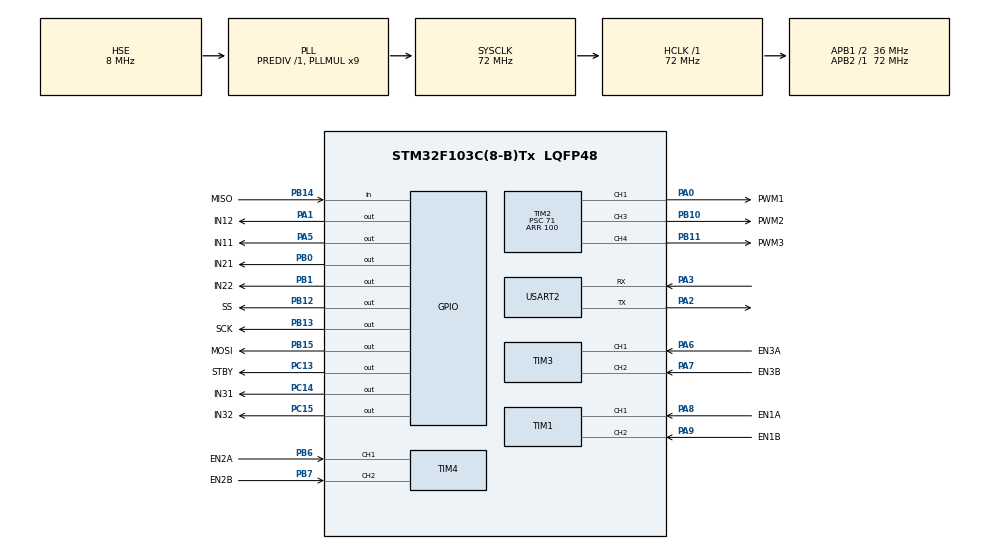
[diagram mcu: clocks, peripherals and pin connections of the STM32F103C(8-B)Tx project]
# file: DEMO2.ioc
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Dma.Request0=USART2_RX
Dma.USART2_RX.0.Direction=DMA_PERIPH_TO_MEMORY
Dma.USART2_RX.0.Instance=DMA1_Channel6
Dma.USART2_RX.0.MemDataAlignment=DMA_MDATAALIGN_BYTE
Dma.USART2_RX.0.MemInc=DMA_MINC_ENABLE
Dma.USART2_RX.0.Mode=DMA_CIRCULAR
Dma.USART2_RX.0.PeriphDataAlignment=DMA_PDATAALIGN_BYTE
Dma.USART2_RX.0.PeriphInc=DMA_PINC_DISABLE
Dma.USART2_RX.0.Priority=DMA_PRIORITY_LOW
Mcu.Family=STM32F1
Mcu.Name=STM32F103C(8-B)Tx
Mcu.Package=LQFP48
NVIC.DMA1_Channel6_IRQn=true\:0\:0\:true\:false\:true\:false\:true\:true
NVIC.PriorityGroup=NVIC_PRIORITYGROUP_4
NVIC.USART2_IRQn=true\:1\:0\:true\:false\:true\:true\:true\:true
PA0-WKUP.GPIO_Label=PWM1
PA0-WKUP.Signal=S_TIM2_CH1_ETR
PA1.GPIO_Label=IN12
PA1.Signal=GPIO_Output
PA13.Mode=Serial_Wire
PA13.Signal=SYS_JTMS-SWDIO
PA14.Mode=Serial_Wire
PA14.Signal=SYS_JTCK-SWCLK
PA2.Mode=Asynchronous
PA2.Signal=USART2_TX
PA3.Mode=Asynchronous
PA3.Signal=USART2_RX
PA5.GPIO_Label=IN11
PA5.Signal=GPIO_Output
PA6.GPIO_Label=EN3A
PA6.Signal=S_TIM3_CH1
PA7.GPIO_Label=EN3B
PA7.Signal=S_TIM3_CH2
PA8.GPIO_Label=EN1A
PA8.Signal=S_TIM1_CH1
PA9.GPIO_Label=EN1B
PA9.Signal=S_TIM1_CH2
PB0.GPIO_Label=IN21
PB0.Signal=GPIO_Output
PB1.GPIO_Label=IN22
PB1.Signal=GPIO_Output
PB10.GPIO_Label=PWM2
PB10.Signal=S_TIM2_CH3
PB11.GPIO_Label=PWM3
PB11.Signal=S_TIM2_CH4
PB12.GPIO_Label=SS
PB12.PinState=GPIO_PIN_SET
PB12.Signal=GPIO_Output
PB13.GPIO_Label=SCK
PB13.PinState=GPIO_PIN_SET
PB13.Signal=GPIO_Output
PB14.GPIO_Label=MISO
PB14.Signal=GPIO_Input
PB15.GPIO_Label=MOSI
PB15.PinState=GPIO_PIN_SET
PB15.Signal=GPIO_Output
PB6.GPIO_Label=EN2A
PB6.Signal=S_TIM4_CH1
PB7.GPIO_Label=EN2B
PB7.Signal=S_TIM4_CH2
PC13-TAMPER-RTC.GPIO_Label=STBY
PC13-TAMPER-RTC.Signal=GPIO_Output
PC14-OSC32_IN.GPIO_Label=IN31
PC14-OSC32_IN.Signal=GPIO_Output
PC15-OSC32_OUT.GPIO_Label=IN32
PC15-OSC32_OUT.Signal=GPIO_Output
PD0-OSC_IN.Mode=HSE-External-Oscillator
PD0-OSC_IN.Signal=RCC_OSC_IN
PD1-OSC_OUT.Mode=HSE-External-Oscillator
PD1-OSC_OUT.Signal=RCC_OSC_OUT
ProjectManager.HeapSize=0x200
ProjectManager.StackSize=0x400
ProjectManager.TargetToolchain=MDK-ARM V5
RCC.AHBFreq_Value=72000000
RCC.APB1CLKDivider=RCC_HCLK_DIV2
RCC.APB1Freq_Value=36000000
RCC.APB1TimFreq_Value=72000000
RCC.APB2Freq_Value=72000000
RCC.APB2TimFreq_Value=72000000
RCC.HCLKFreq_Value=72000000
RCC.PLLMUL=RCC_PLL_MUL9
RCC.PLLSourceVirtual=RCC_PLLSOURCE_HSE
RCC.SYSCLKFreq_VALUE=72000000
RCC.SYSCLKSource=RCC_SYSCLKSOURCE_PLLCLK
RCC.USBFreq_Value=72000000
SH.S_TIM1_CH1.0=TIM1_CH1,Encoder_Interface
SH.S_TIM1_CH2.0=TIM1_CH2,Encoder_Interface
SH.S_TIM2_CH1_ETR.0=TIM2_CH1,PWM Generation1 CH1
SH.S_TIM2_CH3.0=TIM2_CH3,PWM Generation3 CH3
SH.S_TIM2_CH4.0=TIM2_CH4,PWM Generation4 CH4
SH.S_TIM3_CH1.0=TIM3_CH1,Encoder_Interface
SH.S_TIM3_CH2.0=TIM3_CH2,Encoder_Interface
SH.S_TIM4_CH1.0=TIM4_CH1,Encoder_Interface
SH.S_TIM4_CH2.0=TIM4_CH2,Encoder_Interface
TIM1.AutoReloadPreload=TIM_AUTORELOAD_PRELOAD_ENABLE
TIM1.EncoderMode=TIM_ENCODERMODE_TI12
TIM2.AutoReloadPreload=TIM_AUTORELOAD_PRELOAD_ENABLE
TIM2.Channel-PWM\ Generation1\ CH1=TIM_CHANNEL_1
TIM2.Channel-PWM\ Generation3\ CH3=TIM_CHANNEL_3
TIM2.Channel-PWM\ Generation4\ CH4=TIM_CHANNEL_4
TIM2.Period=100
TIM2.Prescaler=71
TIM3.AutoReloadPreload=TIM_AUTORELOAD_PRELOAD_ENABLE
TIM3.EncoderMode=TIM_ENCODERMODE_TI12
TIM4.AutoReloadPreload=TIM_AUTORELOAD_PRELOAD_ENABLE
TIM4.EncoderMode=TIM_ENCODERMODE_TI12
USART2.VirtualMode=VM_ASYNC
VP_TIM2_VS_ClockSourceINT.Mode=Internal
board=custom

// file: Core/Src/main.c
/* USER CODE BEGIN Header */
/**
  ******************************************************************************
  * @file           : main.c
  * @brief          : Main program body
  ******************************************************************************
  * @attention
  *
  * Copyright (c) 2023 STMicroelectronics.
  * All rights reserved.
  *
  * This software is licensed under terms that can be found in the LICENSE file
  * in the root directory of this software component.
  * If no LICENSE file comes with this software, it is provided AS-IS.
  *
  ******************************************************************************
  */
/* USER CODE END Header */
#include "main.h"
#include "pwm.h"
#include "stdio.h"
#include <math.h>
//receive transmit
uint8_t RxBuffer[13];
char TxBuffer[12];
uint16_t i;
uint8_t R=100;
uint8_t r=29;

//input value
//encoder motor value
encoder MOTOR1 = {0,0,0};
encoder MOTOR2 = {0,0,0};
encoder MOTOR3 = {0,0,0};

//PID value
PID PID_1={0.761,21.798,0,0,0,0,0};
PID PID_2={0.809,22.685,0,0,0,0,0};
PID PID_3={0.848,23.505,0,0,0,0,0};

//output value
bot bot1 = {0,0,0};
bot bot2 = {0,0,0};
bot bot3 = {0,0,0};
uint8_t predir0=0,dir0=0;
//reading value
uint32_t timstart;
uint8_t count=30;
uint8_t countt=0;
TIM_HandleTypeDef htim1;
TIM_HandleTypeDef htim2;
TIM_HandleTypeDef htim3;
TIM_HandleTypeDef htim4;

UART_HandleTypeDef huart2;
DMA_HandleTypeDef hdma_usart2_rx;

void SystemClock_Config(void);
static void MX_GPIO_Init(void);
static void MX_DMA_Init(void);
static void MX_TIM1_Init(void);
static void MX_TIM2_Init(void);
static void MX_TIM3_Init(void);
static void MX_TIM4_Init(void);
static void MX_USART2_UART_Init(void);
void receive_value(bot* m1,bot* m2, bot* m3);

int main(void)
{

  /* MCU Configuration--------------------------------------------------------*/

  /* Reset of all peripherals, Initializes the Flash interface and the Systick. */
  HAL_Init();

  /* Configure the system clock */
  SystemClock_Config();

  /* Initialize all configured peripherals */
  MX_GPIO_Init();
  MX_DMA_Init();
  MX_TIM1_Init();
  MX_TIM2_Init();
  MX_TIM3_Init();
  MX_TIM4_Init();
  MX_USART2_UART_Init();
  /* USER CODE BEGIN 2 */
	HAL_TIM_Encoder_Start(&htim1, TIM_CHANNEL_ALL);
	HAL_TIM_Encoder_Start(&htim2, TIM_CHANNEL_ALL);
	HAL_TIM_Encoder_Start(&htim3, TIM_CHANNEL_ALL);
	HAL_TIM_Encoder_Start(&htim4, TIM_CHANNEL_ALL);
	HAL_TIM_PWM_Start(&htim2,TIM_CHANNEL_1);
	HAL_TIM_PWM_Start(&htim2,TIM_CHANNEL_3);
	HAL_TIM_PWM_Start(&htim2,TIM_CHANNEL_4);
	HAL_UART_Receive_DMA(&huart2, RxBuffer, 13);
  /* USER CODE END 2 */

  /* Infinite loop */
  /* USER CODE BEGIN WHILE */
	timstart = HAL_GetTick();
  while (1)
  {
    /* USER CODE END WHILE */
		timeinterrupt();
  }
}
/**
  * @brief Receive value using UART interface
  * @unit RPM
  * @retval uint8_t
  */
void receive_value(bot* m1,bot* m2, bot* m3)
{
	predir0=dir0;
	m1->dir=RxBuffer[0]-48;
	m1->vel=(RxBuffer[1]-48)*100+(RxBuffer[2]-48)*10+(RxBuffer[3]-48)-100;
	m2->dir=RxBuffer[4]-48;
	m2->vel=(RxBuffer[5]-48)*100+(RxBuffer[6]-48)*10+(RxBuffer[7]-48)-100;
	m3->dir=RxBuffer[8]-48;
	m3->vel=(RxBuffer[9]-48)*100+(RxBuffer[10]-48)*10+(RxBuffer[11]-48)-100;
	dir0=RxBuffer[12]-48;
	if (m1->vel>333) m1->vel=0;
	if (m2->vel>333) m2->vel=0;
	if (m3->vel>333) m3->vel=0;
}

/**
  * @brief Transmit velocity value to ROS
  * @unit void
  */

void vel_convert(char* vel_pub)
{
	if (bot1.dir == 0) bot1.cd = '0'; else bot1.cd = '1';
	if (bot2.dir == 0) bot2.cd = '0'; else bot2.cd = '1';
	if (bot3.dir == 0) bot3.cd = '0'; else bot3.cd = '1';
	bot1.iw=round(MOTOR1.w+100);
	bot2.iw=round(MOTOR2.w+100);
	bot3.iw=round(MOTOR3.w+100);
	sprintf(vel_pub, "%c%d%c%d%c%d", bot1.cd, bot1.iw, bot2.cd, bot2.iw, bot3.cd, bot3.iw);
	HAL_UART_Transmit_IT(&huart2, vel_pub, 12);
}

/**
  * @brief Systick Timer Interrupt after 0.01s
  * @unit second
  */
void timeinterrupt(void)
{
  uint32_t wait = 10;

  /* Add a freq to guarantee minimum wait */
  if (wait < HAL_MAX_DELAY)
  {
    wait += (uint32_t)(uwTickFreq);
  }
  if ((HAL_GetTick() - timstart) == wait)
  {
		receive_value(&bot1,&bot2,&bot3);
		if ((dir0==1 && predir0==2) || (dir0==2 && predir0==1))	count=0;
		if (count<20)
		{
			ballkeeping(dir0); // 2 - len(da bong) , 1- xuong(do bong)
			count++;
		}
		else 	ballkeeping(3);
		encoder_reading(&MOTOR1,&MOTOR2,&MOTOR3);
		bot1.pulse = PID_motor(&PID_1,bot1.vel,&MOTOR1)*10;
		bot2.pulse = PID_motor(&PID_2,bot2.vel,&MOTOR2)*10;
		bot3.pulse = PID_motor(&PID_3,bot3.vel,&MOTOR3)*10;
		control(bot1.pulse,bot2.pulse,bot3.pulse,bot1.dir,bot2.dir,bot3.dir);
		if (countt>=10)
			{
				vel_convert(TxBuffer);
				countt=0;
			}
		else countt++;
		timstart = HAL_GetTick();
  }
}
void HAL_UART_TxCpltCallback(UART_HandleTypeDef *huart)
{
   // do nothing here
}
void SystemClock_Config(void)
{
  RCC_OscInitTypeDef RCC_OscInitStruct = {0};
  RCC_ClkInitTypeDef RCC_ClkInitStruct = {0};

  /** Initializes the RCC Oscillators according to the specified parameters
  * in the RCC_OscInitTypeDef structure.
  */
  RCC_OscInitStruct.OscillatorType = RCC_OSCILLATORTYPE_HSE;
  RCC_OscInitStruct.HSEState = RCC_HSE_ON;
  RCC_OscInitStruct.HSEPredivValue = RCC_HSE_PREDIV_DIV1;
  RCC_OscInitStruct.HSIState = RCC_HSI_ON;
  RCC_OscInitStruct.PLL.PLLState = RCC_PLL_ON;
  RCC_OscInitStruct.PLL.PLLSource = RCC_PLLSOURCE_HSE;
  RCC_OscInitStruct.PLL.PLLMUL = RCC_PLL_MUL9;
  if (HAL_RCC_OscConfig(&RCC_OscInitStruct) != HAL_OK)
  {
    Error_Handler();
  }

  /** Initializes the CPU, AHB and APB buses clocks
  */
  RCC_ClkInitStruct.ClockType = RCC_CLOCKTYPE_HCLK|RCC_CLOCKTYPE_SYSCLK
                              |RCC_CLOCKTYPE_PCLK1|RCC_CLOCKTYPE_PCLK2;
  RCC_ClkInitStruct.SYSCLKSource = RCC_SYSCLKSOURCE_PLLCLK;
  RCC_ClkInitStruct.AHBCLKDivider = RCC_SYSCLK_DIV1;
  RCC_ClkInitStruct.APB1CLKDivider = RCC_HCLK_DIV2;
  RCC_ClkInitStruct.APB2CLKDivider = RCC_HCLK_DIV1;

  if (HAL_RCC_ClockConfig(&RCC_ClkInitStruct, FLASH_LATENCY_2) != HAL_OK)
  {
    Error_Handler();
  }
}

static void MX_TIM1_Init(void)
{

  TIM_Encoder_InitTypeDef sConfig = {0};
  TIM_MasterConfigTypeDef sMasterConfig = {0};

  htim1.Instance = TIM1;
  htim1.Init.Prescaler = 0;
  htim1.Init.CounterMode = TIM_COUNTERMODE_UP;
  htim1.Init.Period = 65535;
  htim1.Init.ClockDivision = TIM_CLOCKDIVISION_DIV1;
  htim1.Init.RepetitionCounter = 0;
  htim1.Init.AutoReloadPreload = TIM_AUTORELOAD_PRELOAD_ENABLE;
  sConfig.EncoderMode = TIM_ENCODERMODE_TI12;
  sConfig.IC1Polarity = TIM_ICPOLARITY_RISING;
  sConfig.IC1Selection = TIM_ICSELECTION_DIRECTTI;
  sConfig.IC1Prescaler = TIM_ICPSC_DIV1;
  sConfig.IC1Filter = 0;
  sConfig.IC2Polarity = TIM_ICPOLARITY_RISING;
  sConfig.IC2Selection = TIM_ICSELECTION_DIRECTTI;
  sConfig.IC2Prescaler = TIM_ICPSC_DIV1;
  sConfig.IC2Filter = 0;
  if (HAL_TIM_Encoder_Init(&htim1, &sConfig) != HAL_OK)
  {
    Error_Handler();
  }
  sMasterConfig.MasterOutputTrigger = TIM_TRGO_RESET;
  sMasterConfig.MasterSlaveMode = TIM_MASTERSLAVEMODE_DISABLE;
  if (HAL_TIMEx_MasterConfigSynchronization(&htim1, &sMasterConfig) != HAL_OK)
  {
    Error_Handler();
  }

}

static void MX_TIM2_Init(void)
{

  TIM_ClockConfigTypeDef sClockSourceConfig = {0};
  TIM_MasterConfigTypeDef sMasterConfig = {0};
  TIM_OC_InitTypeDef sConfigOC = {0};

  htim2.Instance = TIM2;
  htim2.Init.Prescaler = 71;
  htim2.Init.CounterMode = TIM_COUNTERMODE_UP;
  htim2.Init.Period = 1000;
  htim2.Init.ClockDivision = TIM_CLOCKDIVISION_DIV1;
  htim2.Init.AutoReloadPreload = TIM_AUTORELOAD_PRELOAD_ENABLE;
  if (HAL_TIM_Base_Init(&htim2) != HAL_OK)
  {
    Error_Handler();
  }
  sClockSourceConfig.ClockSource = TIM_CLOCKSOURCE_INTERNAL;
  if (HAL_TIM_ConfigClockSource(&htim2, &sClockSourceConfig) != HAL_OK)
  {
    Error_Handler();
  }
  if (HAL_TIM_PWM_Init(&htim2) != HAL_OK)
  {
    Error_Handler();
  }
  sMasterConfig.MasterOutputTrigger = TIM_TRGO_RESET;
  sMasterConfig.MasterSlaveMode = TIM_MASTERSLAVEMODE_DISABLE;
  if (HAL_TIMEx_MasterConfigSynchronization(&htim2, &sMasterConfig) != HAL_OK)
  {
    Error_Handler();
  }
  sConfigOC.OCMode = TIM_OCMODE_PWM1;
  sConfigOC.Pulse = 0;
  sConfigOC.OCPolarity = TIM_OCPOLARITY_HIGH;
  sConfigOC.OCFastMode = TIM_OCFAST_DISABLE;
  if (HAL_TIM_PWM_ConfigChannel(&htim2, &sConfigOC, TIM_CHANNEL_1) != HAL_OK)
  {
    Error_Handler();
  }
	 if (HAL_TIM_PWM_ConfigChannel(&htim2, &sConfigOC, TIM_CHANNEL_2) != HAL_OK)
  {
    Error_Handler();
  }
  if (HAL_TIM_PWM_ConfigChannel(&htim2, &sConfigOC, TIM_CHANNEL_3) != HAL_OK)
  {
    Error_Handler();
  }
  if (HAL_TIM_PWM_ConfigChannel(&htim2, &sConfigOC, TIM_CHANNEL_4) != HAL_OK)
  {
    Error_Handler();
  }
  HAL_TIM_MspPostInit(&htim2);

}

static void MX_TIM3_Init(void)
{

  TIM_Encoder_InitTypeDef sConfig = {0};
  TIM_MasterConfigTypeDef sMasterConfig = {0};

  htim3.Instance = TIM3;
  htim3.Init.Prescaler = 0;
  htim3.Init.CounterMode = TIM_COUNTERMODE_UP;
  htim3.Init.Period = 65535;
  htim3.Init.ClockDivision = TIM_CLOCKDIVISION_DIV1;
  htim3.Init.AutoReloadPreload = TIM_AUTORELOAD_PRELOAD_ENABLE;
  sConfig.EncoderMode = TIM_ENCODERMODE_TI12;
  sConfig.IC1Polarity = TIM_ICPOLARITY_RISING;
  sConfig.IC1Selection = TIM_ICSELECTION_DIRECTTI;
  sConfig.IC1Prescaler = TIM_ICPSC_DIV1;
  sConfig.IC1Filter = 0;
  sConfig.IC2Polarity = TIM_ICPOLARITY_RISING;
  sConfig.IC2Selection = TIM_ICSELECTION_DIRECTTI;
  sConfig.IC2Prescaler = TIM_ICPSC_DIV1;
  sConfig.IC2Filter = 0;
  if (HAL_TIM_Encoder_Init(&htim3, &sConfig) != HAL_OK)
  {
    Error_Handler();
  }
  sMasterConfig.MasterOutputTrigger = TIM_TRGO_RESET;
  sMasterConfig.MasterSlaveMode = TIM_MASTERSLAVEMODE_DISABLE;
  if (HAL_TIMEx_MasterConfigSynchronization(&htim3, &sMasterConfig) != HAL_OK)
  {
    Error_Handler();
  }

}

static void MX_TIM4_Init(void)
{

  TIM_Encoder_InitTypeDef sConfig = {0};
  TIM_MasterConfigTypeDef sMasterConfig = {0};

  htim4.Instance = TIM4;
  htim4.Init.Prescaler = 0;
  htim4.Init.CounterMode = TIM_COUNTERMODE_UP;
  htim4.Init.Period = 65535;
  htim4.Init.ClockDivision = TIM_CLOCKDIVISION_DIV1;
  htim4.Init.AutoReloadPreload = TIM_AUTORELOAD_PRELOAD_ENABLE;
  sConfig.EncoderMode = TIM_ENCODERMODE_TI12;
  sConfig.IC1Polarity = TIM_ICPOLARITY_RISING;
  sConfig.IC1Selection = TIM_ICSELECTION_DIRECTTI;
  sConfig.IC1Prescaler = TIM_ICPSC_DIV1;
  sConfig.IC1Filter = 0;
  sConfig.IC2Polarity = TIM_ICPOLARITY_RISING;
  sConfig.IC2Selection = TIM_ICSELECTION_DIRECTTI;
  sConfig.IC2Prescaler = TIM_ICPSC_DIV1;
  sConfig.IC2Filter = 0;
  if (HAL_TIM_Encoder_Init(&htim4, &sConfig) != HAL_OK)
  {
    Error_Handler();
  }
  sMasterConfig.MasterOutputTrigger = TIM_TRGO_RESET;
  sMasterConfig.MasterSlaveMode = TIM_MASTERSLAVEMODE_DISABLE;
  if (HAL_TIMEx_MasterConfigSynchronization(&htim4, &sMasterConfig) != HAL_OK)
  {
    Error_Handler();
  }

}

static void MX_USART2_UART_Init(void)
{

  huart2.Instance = USART2;
  huart2.Init.BaudRate = 115200;
  huart2.Init.WordLength = UART_WORDLENGTH_8B;
  huart2.Init.StopBits = UART_STOPBITS_1;
  huart2.Init.Parity = UART_PARITY_NONE;
  huart2.Init.Mode = UART_MODE_TX_RX;
  huart2.Init.HwFlowCtl = UART_HWCONTROL_NONE;
  huart2.Init.OverSampling = UART_OVERSAMPLING_16;
  if (HAL_UART_Init(&huart2) != HAL_OK)
  {
    Error_Handler();
  }

}

static void MX_DMA_Init(void)
{

  /* DMA controller clock enable */
  __HAL_RCC_DMA1_CLK_ENABLE();

  /* DMA interrupt init */
  /* DMA1_Channel6_IRQn interrupt configuration */
  HAL_NVIC_SetPriority(DMA1_Channel6_IRQn, 0, 0);
  HAL_NVIC_EnableIRQ(DMA1_Channel6_IRQn);

}

static void MX_GPIO_Init(void)
{
  GPIO_InitTypeDef GPIO_InitStruct = {0};

  /* GPIO Ports Clock Enable */
  __HAL_RCC_GPIOC_CLK_ENABLE();
  __HAL_RCC_GPIOD_CLK_ENABLE();
  __HAL_RCC_GPIOA_CLK_ENABLE();
  __HAL_RCC_GPIOB_CLK_ENABLE();

  /*Configure GPIO pin Output Level */
  HAL_GPIO_WritePin(GPIOC, STBY_Pin|IN31_Pin|IN32_Pin, GPIO_PIN_RESET);

  /*Configure GPIO pin Output Level */
  HAL_GPIO_WritePin(GPIOA, IN12_Pin|IN11_Pin|IN22_Pin|GPIO_PIN_10|GPIO_PIN_11|GPIO_PIN_15, GPIO_PIN_RESET);

  /*Configure GPIO pin Output Level */
  HAL_GPIO_WritePin(GPIOB, IN21_Pin|GPIO_PIN_4|GPIO_PIN_5, GPIO_PIN_RESET);

  /*Configure GPIO pin Output Level */
  HAL_GPIO_WritePin(GPIOB, SS_Pin|SCK_Pin|MOSI_Pin, GPIO_PIN_SET);

  /*Configure GPIO pins : STBY_Pin IN31_Pin IN32_Pin */
  GPIO_InitStruct.Pin = STBY_Pin|IN31_Pin|IN32_Pin;
  GPIO_InitStruct.Mode = GPIO_MODE_OUTPUT_PP;
  GPIO_InitStruct.Pull = GPIO_NOPULL;
  GPIO_InitStruct.Speed = GPIO_SPEED_FREQ_LOW;
  HAL_GPIO_Init(GPIOC, &GPIO_InitStruct);

  /*Configure GPIO pins : IN12_Pin IN11_Pin */
  GPIO_InitStruct.Pin = IN12_Pin|IN11_Pin|IN22_Pin;
  GPIO_InitStruct.Mode = GPIO_MODE_OUTPUT_PP;
  GPIO_InitStruct.Pull = GPIO_NOPULL;
  GPIO_InitStruct.Speed = GPIO_SPEED_FREQ_LOW;
  HAL_GPIO_Init(GPIOA, &GPIO_InitStruct);

  /*Configure GPIO pins : IN21_Pin IN22_Pin SS_Pin SCK_Pin
                           MOSI_Pin */
  GPIO_InitStruct.Pin = IN21_Pin|SS_Pin|SCK_Pin
                          |MOSI_Pin|GPIO_PIN_4|GPIO_PIN_5;
  GPIO_InitStruct.Mode = GPIO_MODE_OUTPUT_PP;
  GPIO_InitStruct.Pull = GPIO_NOPULL;
  GPIO_InitStruct.Speed = GPIO_SPEED_FREQ_LOW;
  HAL_GPIO_Init(GPIOB, &GPIO_InitStruct);

  /*Configure GPIO pin : MISO_Pin */
  GPIO_InitStruct.Pin = MISO_Pin;
  GPIO_InitStruct.Mode = GPIO_MODE_INPUT;
  GPIO_InitStruct.Pull = GPIO_NOPULL;
  HAL_GPIO_Init(MISO_GPIO_Port, &GPIO_InitStruct);

}

void Error_Handler(void)
{
  __disable_irq();
  while (1)
  {
  }
}
